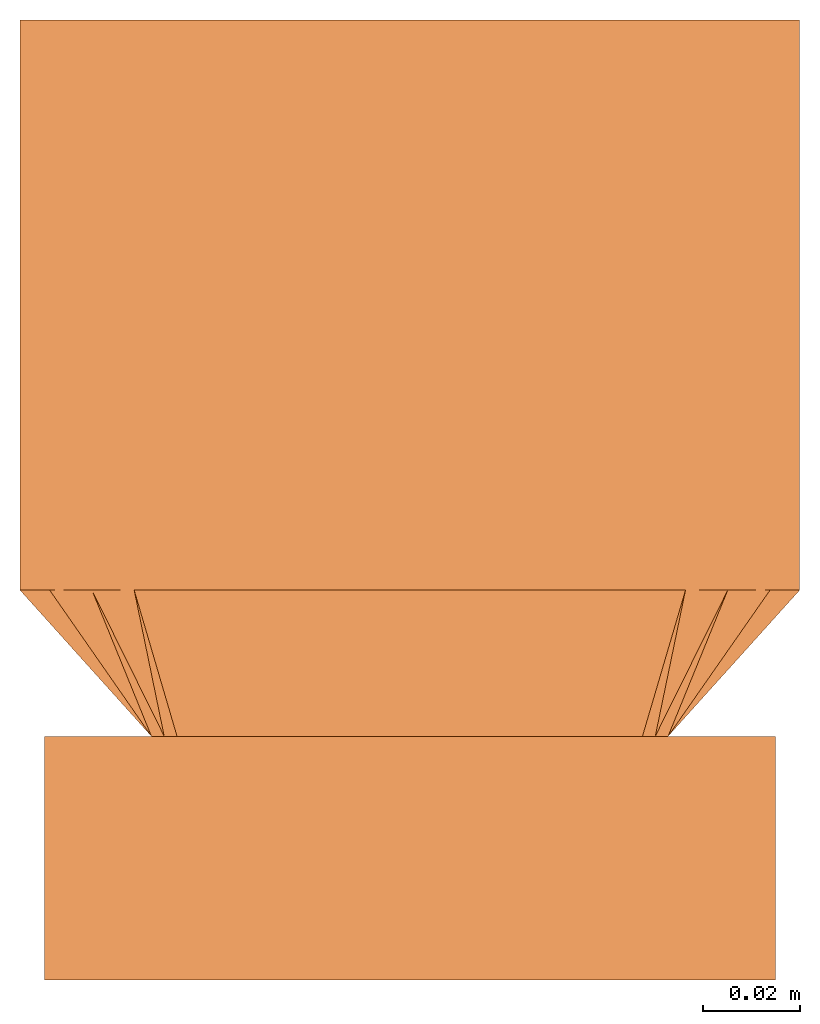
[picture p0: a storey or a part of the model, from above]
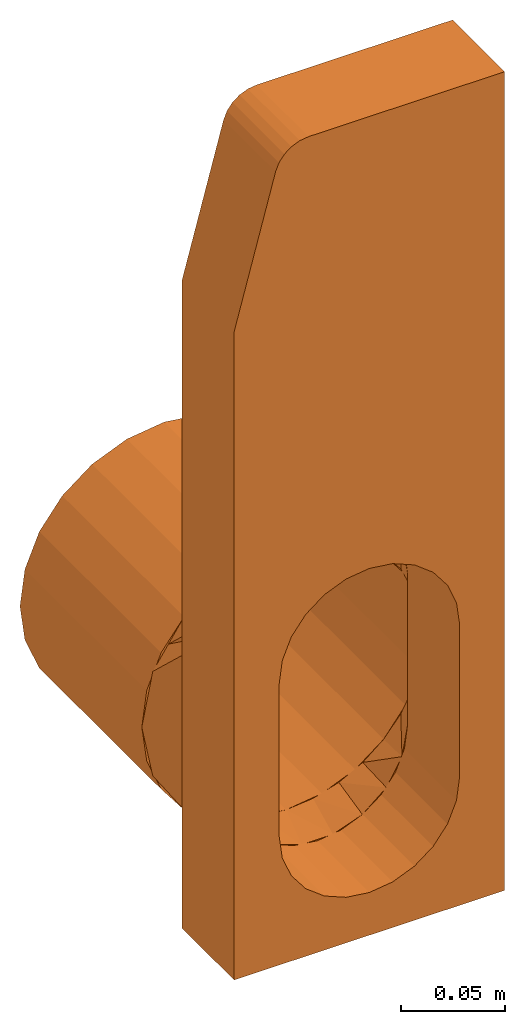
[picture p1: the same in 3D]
Properties of the parts of a building model (IFC2X3)

# File
Description: ViewDefinition [CoordinationView]
File name: 4939 - LH inlet or outlet end cap.ifc
Time: 2013-09-18T16:25:27
Written by: Autodesk Revit 2013
Made in: 20120221_2030(x64)

# IfcProject, Project Number
LongName: Project Name; Phase: Project Status

# IfcSite, Default
RefLatitude: 42, 21, 30, 344238; RefLongitude: -71, -3, -35, -194702; RefElevation: 0 mm

# IfcBuilding
Pset_BuildingCommon - NumberOfStoreys: 2
Other - Client Name: Owner; Project Status: Project Status; Project Name: Project Name; Project Address: Enter address here; Project Issue Date: Issue Date; Project Number: Project Number

# IfcBuildingStorey (2)
Graphics - Line Pattern: Center; Symbol at End 2 Default: yes; Symbol at End 1 Default: no; Color: 0; Symbol: M_Level Head - Circle: M_Level Head - Circle; Line Weight: 1
Constraints - Elevation Base: 0
Dimensions - Computation Height: 0 mm
Identity Data - Structural: no; Building Story: yes
Name | LongName = Name | Elevation (mm) = Constraints, Elevation (mm)
T.O. Fnd. Wall | T.O. Fnd. Wall | -300
Level 1 | Level 1 | 0

# IfcBuildingElementProxy: 4939 - LH inlet/outlet end cap, Civil-Drainage-Channel-ACO-KerbDrain-HB480(amar):4939 - LH inlet/outlet end cap:4939 - LH inlet/outlet end cap:481515
In: T.O. Fnd. Wall
Material: Acetal Resin, Black, ACO Polymer Concrete.
Green Building Properties - Access Cover/Frame Recycled Material Content: N/A; Channel Recycled Material Content: N/A; Channel Recyclable: N/A; Access Cover/Frame Recyclable: N/A; End Cap Recyclable: Fully recyclable; End Cap Recycled Material Content: 20% minimum
Materials and Finishes - Channel Colour: N/A; Access Cover/Frame Colour: N/A; Channel Material: N/A; Connection Pipe Material: Medium Density Polyethylene; Access Cover/Frame Material: N/A; Connection Pipe Material Colour: Black; End Cap Material: Vienite® Synthetic Resin Concrete; Access Cover/Frame Finish: N/A; End Cap Colour: Grey
Construction - HB480-500: no; KDHB480 500_blindunit: no; Centre Stone: no; RH BS transition kerb: no; LH drop kerb: no; 10-8m external mitre: no; LH inlet/outlet end cap: yes; 7-6m external mitre: no; Bus stop kerb: no; 25-11m external mitre: no; Junction access unit: no; Junction channel: no; Junction end cap: no; Closing end cap: no; RH inlet/outlet end cap: no; LH BS transition kerb: no; 25-11m internal mitre: no; cable loop: no; RH drop kerb: no; perforated centre stone: no; Access Unit: no
Other - Revision: 1; CreatedBy: www.aco.co.uk
Constraints - Level: Level: Level 1; Moves With Nearby Elements: no
Phasing - Phase Created: Phase 1
Dimensions - Volume: 2938034 mm3; Mitre Void Start: -6546 mm; Void Length: 50 mm; Mitre Void End: -6549 mm; Straight Void Start: 0 mm; Mitre Small End: 487 mm; Mitre Long end: 500 mm; Junction End: 2 mm; Void Width: 150 mm; Void Depth: -355 mm; Junction Start: 0 mm; Void End I/O: 155.1 mm; Void Start I/O: -5.1 mm; I/O endcap void depth: 333.621 mm; junction void depth: 2000 mm
Pset_BuildingElementProxyCommon - Reference: 4939 - LH inlet/outlet end cap
Data - Concrete Surround Volume - Load Class A 15 - D 400 - Grass or Asphalt Pavement: N/A; Product Standard: N/A; Concrete Surround Volume - Load Class A 15 - D 400 - Concrete Pavement: N/A; Invert Depth: N/A; Product Dimensions: 50mm x 150mm x 480mm (LxWxH); Drainage Slot Intake area: N/A; Load Class: N/A; Channel C.S.A: N/A; Hydraulic Performance: N/A; Installation - Concrete Grade: N/A; Drainage Slot Width: N/A; Connection Pipe O.D: Ø160mm; Product Weight: 5.9 Kg; ACO Hydraulic Design Software: N/A
General - SerialNumber: 0.000000; TagNumber: 0.000000
Identity Data - Installation guidelines: http://www.aco.co.uk/download.php?id=120 http://www.aco.co.uk/download.php?id=120; e-mail Sales: customersupport@aco.co.uk; e-mail Technical: technical@aco.co.uk; Cost: 0; Product brochure: http://www.aco.co.uk/download.php?id=120; OmniClass Number: 23.70.50.24; Type Comments: ACO KerbDrain HB480 half battered LH outlet end cap; Manufacturer: ACO Technologies plc - ACO Water Management Division; Maintenance guidelines: http://www.aco.co.uk/download.php?id=120; Price: POA - contact ACO; OmniClass Title: Rainwater Removal; Assembly Description: Rain Water Drainage; Product Code: 4939; Telephone: +44 (0)1462 816666; Product Page URL: http://www.aco.co.uk/product_detail.php?id=3; URL: www.aco.co.uk; Model: ACO KerbDrain HB480; Model Description: Combined kerb and drainage system; Fax: +44 (0)1462 815895; Address: ACO Business Park, Hitchin Road, Shefford, Bedfordshire, United Kingdom SG17 5TE; Assembly Code: D2040

# IfcOpeningElement: Opening (3)
In: Level 1
Dimensions - Volume: 2354181020 mm3; Area: 5901750 mm2; Perimeter: 9790 mm; Thickness: 400 mm
Constraints - Room Bounding: yes; Height Offset From Level: 0 mm; Related to Mass: no; Level: Level: Level 1
Phasing - Phase Created: Phase 1
Structural - Enable Analytical Model: no; Structural: no
Analytical Properties - Thermal Resistance (R): 0.477897; Heat Transfer Coefficient (U): 2.0925; Roughness: 1; Absorptance: 0.1; Thermal mass: 543920
Graphics - Coarse Scale Fill Color: 0
Construction - Function: 0; Default Thickness: 400 mm
Materials and Finishes - Structural Material: Earth

# IfcSlab: Floor:Generic Floor - 400mm, Floor:Generic Floor - 400mm:136426
In: Level 1
PredefinedType: FLOOR; Material: Earth 400 mm
Dimensions - Volume: 2354181020 mm3; Area: 5901750 mm2; Perimeter: 9790 mm; Thickness: 400 mm
Constraints - Room Bounding: yes; Height Offset From Level: 0 mm; Related to Mass: no; Level: Level: Level 1
Phasing - Phase Created: Phase 1
Structural - Enable Analytical Model: no; Structural: no
Pset_SlabCommon - Reference: Generic Floor - 400mm; IsExternal: no; LoadBearing: yes
Analytical Properties - Thermal Resistance (R): 0.477897; Heat Transfer Coefficient (U): 2.0925; Roughness: 1; Absorptance: 0.1; Thermal mass: 543920
Graphics - Coarse Scale Fill Color: 0
Construction - Function: 0; Default Thickness: 400 mm
Materials and Finishes - Structural Material: Earth
